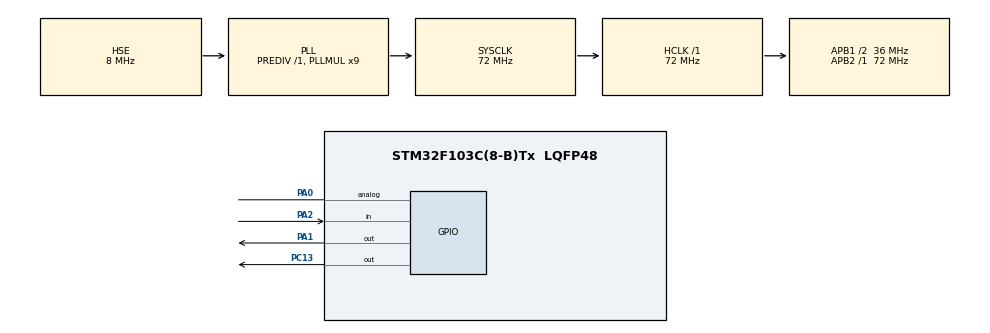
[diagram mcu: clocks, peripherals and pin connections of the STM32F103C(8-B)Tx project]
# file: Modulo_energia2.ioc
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Mcu.Family=STM32F1
Mcu.Name=STM32F103C(8-B)Tx
Mcu.Package=LQFP48
NVIC.PriorityGroup=NVIC_PRIORITYGROUP_4
NVIC.TIM2_IRQn=true\:0\:0\:false\:false\:true\:true\:true
PA0-WKUP.Signal=GPIO_Analog
PA1.Signal=GPIO_Output
PA2.Signal=GPIO_Input
PC13-TAMPER-RTC.Signal=GPIO_Output
PD0-OSC_IN.Mode=HSE-External-Oscillator
PD0-OSC_IN.Signal=RCC_OSC_IN
PD1-OSC_OUT.Mode=HSE-External-Oscillator
PD1-OSC_OUT.Signal=RCC_OSC_OUT
ProjectManager.HeapSize=0x200
ProjectManager.StackSize=0x400
ProjectManager.TargetToolchain=TrueSTUDIO
RCC.AHBFreq_Value=72000000
RCC.APB1CLKDivider=RCC_HCLK_DIV2
RCC.APB1Freq_Value=36000000
RCC.APB1TimFreq_Value=72000000
RCC.APB2Freq_Value=72000000
RCC.APB2TimFreq_Value=72000000
RCC.HCLKFreq_Value=72000000
RCC.PLLMUL=RCC_PLL_MUL9
RCC.PLLSourceVirtual=RCC_PLLSOURCE_HSE
RCC.SYSCLKFreq_VALUE=72000000
RCC.SYSCLKSource=RCC_SYSCLKSOURCE_PLLCLK
RCC.USBFreq_Value=72000000
TIM2.Period=999
TIM2.Prescaler=7999
VP_SYS_VS_ND.Mode=No_Debug
VP_TIM2_VS_ClockSourceINT.Mode=Internal
board=custom

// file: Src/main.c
/*

	 .d88888b.  8888888b.  8888888888 888b     d888 888     888  .d8888b.
	d88P" "Y88b 888   Y88b 888        8888b   d8888 888     888 d88P  Y88b
	888     888 888    888 888        88888b.d88888 888     888 Y88b.
	888     888 888   d88P 8888888    888Y88888P888 888     888  "Y888b.
	888     888 8888888P"  888        888 Y888P 888 888     888     "Y88b.
	888     888 888 T88b   888        888  Y8P  888 888     888       "888
	Y88b. .d88P 888  T88b  888        888   "   888 Y88b. .d88P Y88b  d88P
	 "Y88888P"  888   T88b 8888888888 888       888  "Y88888P"   "Y8888P"

  ******************************************************************************
  *        M  O  D  U  L  O     E  N  E  R  G  I  A - Versão 2 - 14/01/2020
  ******************************************************************************

	CAN GPIO Configuration
    PB8  -> CAN_RX
    PB9  -> CAN_TX

    PB7  -> LED Azul

    PA2  ->  Chave magnétca (Sensor)
    PA1  ->  Comando para o Relé

   __________________________
  |                          |
  |        Tabela IDs        |
  |__________________________|
  | Desligar:          0x001 |
  | Comando:           0x003 |
  | Pergunta Dados:    0x005 |
  |                          |
  | Resposta Motor:    0x004 |
  |	Resposta Energia:  0x006 |
  | Resposta Sensores: 0x008 |
  |__________________________|

/* USER CODE BEGIN Header */
/**
  ******************************************************************************
  * @file           : main.c
  * @brief          : Main program body
  ******************************************************************************
  * @attention
  *
  * <h2><center>&copy; Copyright (c) 2019 STMicroelectronics.
  * All rights reserved.</center></h2>
  *
  * This software component is licensed by ST under BSD 3-Clause license,
  * the "License"; You may not use this file except in compliance with the
  * License. You may obtain a copy of the License at:
  *                        opensource.org/licenses/BSD-3-Clause
  *
  ******************************************************************************
  */
/* USER CODE END Header */

#include "main.h"

/* USER CODE BEGIN Includes */
#include "MY_NRF24.h"
/* USER CODE END Includes */

TIM_HandleTypeDef htim2;
SPI_HandleTypeDef hspi1;

void SystemClock_Config(void);
static void MX_GPIO_Init(void);
static void MX_TIM2_Init(void);

/* USER CODE BEGIN 0 */
uint64_t TxpipeAddrs = 0xe7e7e7e7e7;
char myTxData[32] = "Tatu bola, te amo!ddd";
/* USER CODE END 0 */

int  cont=0;

int main(void)
{

  /* MCU Configuration--------------------------------------------------------*/

  /* Reset of all peripherals, Initializes the Flash interface and the Systick. */
  HAL_Init();

  /* Configure the system clock */
  SystemClock_Config();

  /* Initialize all configured peripherals */
  MX_GPIO_Init();
  MX_TIM2_Init();

  NRF24_begin(GPIOA,GPIO_PIN_3,GPIO_PIN_4, hspi1);
  //nrf24_DebugUART_Init(huart1);

  //*** TRANSMIT - NO ACK ***//
  NRF24_stopListening();
  NRF24_openWritingPipe(TxpipeAddrs);
  NRF24_setChannel(3);
  NRF24_setDataRate(RF24_250KBPS);
  NRF24_setPALevel(RF24_PA_0dB); // máximo RF24_PA_0dB
  NRF24_setPayloadSize(32);

  HAL_TIM_Base_Start_IT(&htim2);

  while (1)
  {

	    /* USER CODE END WHILE */
	    HAL_GPIO_TogglePin(GPIOC,GPIO_PIN_13);

	    if (NRF24_write(myTxData,32)){
	    	HAL_UART_Transmit(&huart1, (uint8_t *)"Transmitted Successfully\r\n", strlen("Transmitted Successfully\r\n"),10);
	    }
	    //printRadioSettings();
	    HAL_Delay(1000);
  }
}

void SystemClock_Config(void)
{
  RCC_OscInitTypeDef RCC_OscInitStruct = {0};
  RCC_ClkInitTypeDef RCC_ClkInitStruct = {0};

  /** Initializes the CPU, AHB and APB busses clocks
  */
  RCC_OscInitStruct.OscillatorType = RCC_OSCILLATORTYPE_HSE;
  RCC_OscInitStruct.HSEState = RCC_HSE_ON;
  RCC_OscInitStruct.HSEPredivValue = RCC_HSE_PREDIV_DIV1;
  RCC_OscInitStruct.HSIState = RCC_HSI_ON;
  RCC_OscInitStruct.PLL.PLLState = RCC_PLL_ON;
  RCC_OscInitStruct.PLL.PLLSource = RCC_PLLSOURCE_HSE;
  RCC_OscInitStruct.PLL.PLLMUL = RCC_PLL_MUL9;
  if (HAL_RCC_OscConfig(&RCC_OscInitStruct) != HAL_OK)
  {
    Error_Handler();
  }
  /** Initializes the CPU, AHB and APB busses clocks
  */
  RCC_ClkInitStruct.ClockType = RCC_CLOCKTYPE_HCLK|RCC_CLOCKTYPE_SYSCLK
                              |RCC_CLOCKTYPE_PCLK1|RCC_CLOCKTYPE_PCLK2;
  RCC_ClkInitStruct.SYSCLKSource = RCC_SYSCLKSOURCE_PLLCLK;
  RCC_ClkInitStruct.AHBCLKDivider = RCC_SYSCLK_DIV1;
  RCC_ClkInitStruct.APB1CLKDivider = RCC_HCLK_DIV2;
  RCC_ClkInitStruct.APB2CLKDivider = RCC_HCLK_DIV1;

  if (HAL_RCC_ClockConfig(&RCC_ClkInitStruct, FLASH_LATENCY_2) != HAL_OK)
  {
    Error_Handler();
  }
}

static void MX_SPI1_Init(void)
{

  /* SPI1 parameter configuration*/
  hspi1.Instance = SPI1;
  hspi1.Init.Mode = SPI_MODE_MASTER;
  hspi1.Init.Direction = SPI_DIRECTION_2LINES;
  hspi1.Init.DataSize = SPI_DATASIZE_8BIT;
  hspi1.Init.CLKPolarity = SPI_POLARITY_LOW;
  hspi1.Init.CLKPhase = SPI_PHASE_1EDGE;
  hspi1.Init.NSS = SPI_NSS_SOFT;
  hspi1.Init.BaudRatePrescaler = SPI_BAUDRATEPRESCALER_32;
  hspi1.Init.FirstBit = SPI_FIRSTBIT_MSB;
  hspi1.Init.TIMode = SPI_TIMODE_DISABLE;
  hspi1.Init.CRCCalculation = SPI_CRCCALCULATION_DISABLE;
  hspi1.Init.CRCPolynomial = 10;
  if (HAL_SPI_Init(&hspi1) != HAL_OK)
  {
    Error_Handler();
  }

}

static void MX_TIM2_Init(void)
{

  TIM_ClockConfigTypeDef sClockSourceConfig = {0};
  TIM_MasterConfigTypeDef sMasterConfig = {0};

  htim2.Instance = TIM2;
  htim2.Init.Prescaler = 35999;
  htim2.Init.CounterMode = TIM_COUNTERMODE_UP;
  htim2.Init.Period = 999;
  htim2.Init.ClockDivision = TIM_CLOCKDIVISION_DIV1;
  htim2.Init.AutoReloadPreload = TIM_AUTORELOAD_PRELOAD_DISABLE;
  if (HAL_TIM_Base_Init(&htim2) != HAL_OK)
  {
    Error_Handler();
  }
  sClockSourceConfig.ClockSource = TIM_CLOCKSOURCE_INTERNAL;
  if (HAL_TIM_ConfigClockSource(&htim2, &sClockSourceConfig) != HAL_OK)
  {
    Error_Handler();
  }
  sMasterConfig.MasterOutputTrigger = TIM_TRGO_RESET;
  sMasterConfig.MasterSlaveMode = TIM_MASTERSLAVEMODE_DISABLE;
  if (HAL_TIMEx_MasterConfigSynchronization(&htim2, &sMasterConfig) != HAL_OK)
  {
    Error_Handler();
  }

}

static void MX_GPIO_Init(void)
{
  GPIO_InitTypeDef GPIO_InitStruct = {0};

  /* GPIO Ports Clock Enable */
  __HAL_RCC_GPIOC_CLK_ENABLE();
  __HAL_RCC_GPIOD_CLK_ENABLE();
  __HAL_RCC_GPIOA_CLK_ENABLE();

  /*Configure GPIO pin Output Level */
  HAL_GPIO_WritePin(GPIOC, GPIO_PIN_13, GPIO_PIN_RESET);

  /*Configure GPIO pin Output Level */
  HAL_GPIO_WritePin(GPIOA, GPIO_PIN_1, GPIO_PIN_RESET);

  /*Configure GPIO pin : PC13 */
  GPIO_InitStruct.Pin = GPIO_PIN_13;
  GPIO_InitStruct.Mode = GPIO_MODE_OUTPUT_PP;
  GPIO_InitStruct.Pull = GPIO_NOPULL;
  GPIO_InitStruct.Speed = GPIO_SPEED_FREQ_LOW;
  HAL_GPIO_Init(GPIOC, &GPIO_InitStruct);

  /*Configure GPIO pin : PA0 */
  GPIO_InitStruct.Pin = GPIO_PIN_0;
  GPIO_InitStruct.Mode = GPIO_MODE_ANALOG;
  HAL_GPIO_Init(GPIOA, &GPIO_InitStruct);

  /*Configure GPIO pin : PA1 */
  GPIO_InitStruct.Pin = GPIO_PIN_1;
  GPIO_InitStruct.Mode = GPIO_MODE_OUTPUT_PP;
  GPIO_InitStruct.Pull = GPIO_NOPULL;
  GPIO_InitStruct.Speed = GPIO_SPEED_FREQ_LOW;
  HAL_GPIO_Init(GPIOA, &GPIO_InitStruct);

  /*Configure GPIO pin : PA2 */
  GPIO_InitStruct.Pin = GPIO_PIN_2;
  GPIO_InitStruct.Mode = GPIO_MODE_INPUT;
  GPIO_InitStruct.Pull = GPIO_NOPULL;
  HAL_GPIO_Init(GPIOA, &GPIO_InitStruct);

  /*Configure GPIO pin Output Level */
  HAL_GPIO_WritePin(GPIOA, GPIO_PIN_3|GPIO_PIN_4, GPIO_PIN_RESET);

  /*Configure GPIO pin : PC13 */
  GPIO_InitStruct.Pin = GPIO_PIN_13;
  GPIO_InitStruct.Mode = GPIO_MODE_OUTPUT_PP;
  GPIO_InitStruct.Pull = GPIO_NOPULL;
  GPIO_InitStruct.Speed = GPIO_SPEED_FREQ_LOW;
  HAL_GPIO_Init(GPIOC, &GPIO_InitStruct);

  /*Configure GPIO pins : PA3 PA4 */
  GPIO_InitStruct.Pin = GPIO_PIN_3|GPIO_PIN_4;
  GPIO_InitStruct.Mode = GPIO_MODE_OUTPUT_PP;
  GPIO_InitStruct.Pull = GPIO_NOPULL;
  GPIO_InitStruct.Speed = GPIO_SPEED_FREQ_LOW;
  HAL_GPIO_Init(GPIOA, &GPIO_InitStruct);

}

HAL_TIM_PeriodElapsedCallback(TIM_HandleTypeDef*htim)
{
	    if (htim->Instance==TIM2){

	    	if (HAL_GPIO_ReadPin(GPIOA,GPIO_PIN_2)){
	    		cont++;
	    		HAL_GPIO_TogglePin(GPIOC, GPIO_PIN_13);

		    	if(cont>= 4){
		    		cont=0;
		    		//HAL_GPIO_WritePin(GPIOC, GPIO_PIN_13, GPIO_PIN_RESET);
		    		HAL_GPIO_WritePin(GPIOA, GPIO_PIN_1, GPIO_PIN_SET);
		    	}
	    	}
	    	else
	    	cont=0;

	    }
}

void Error_Handler(void)
{
}

/************************ (C) COPYRIGHT STMicroelectronics *****END OF FILE****/
